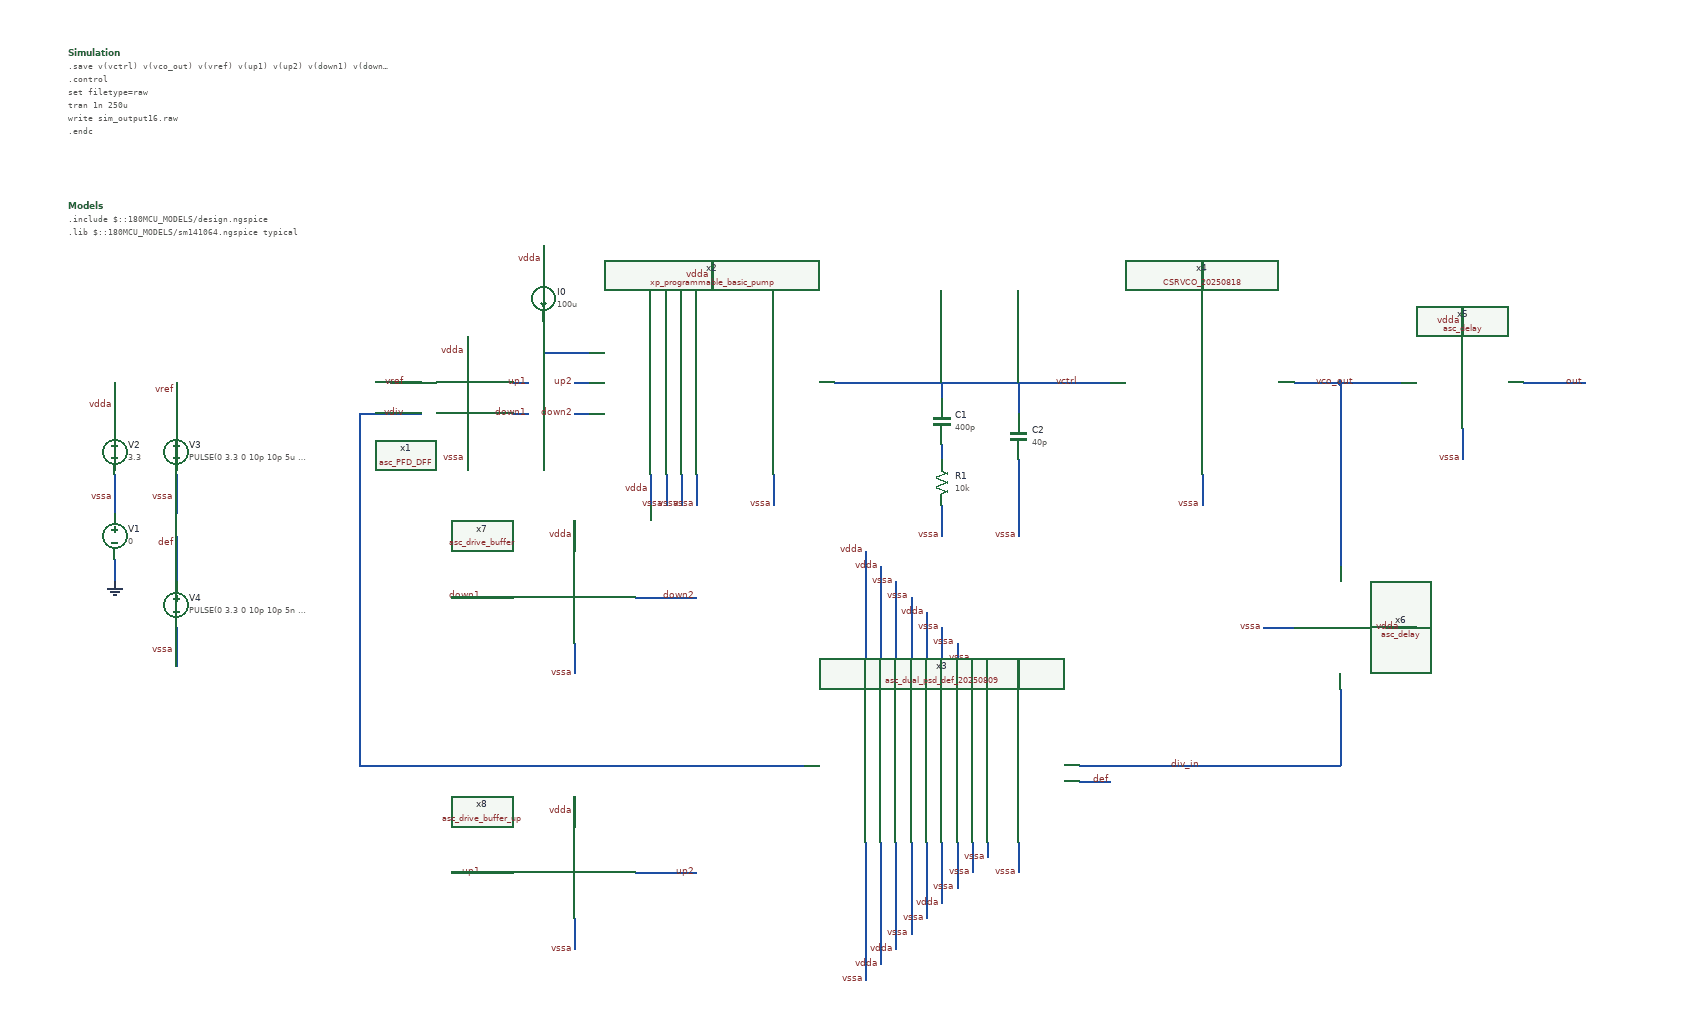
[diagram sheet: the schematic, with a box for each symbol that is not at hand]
v {xschem version=3.4.7 file_version=1.2}
G {}
K {}
V {}
S {}
E {}
N 200 -570 200 -540 {lab=GND}
N 200 -680 200 -630 {lab=vssa}
N 200 -800 200 -740 {lab=vdda}
N 280 -680 280 -630 {lab=vssa}
N 280 -800 280 -740 {lab=vref}
N 560 -800 600 -800 {lab=vref}
N 560 -760 600 -760 {lab=vdiv}
N 660 -860 660 -820 {lab=vdda}
N 660 -740 660 -700 {lab=vssa}
N 1180 -800 1220 -800 {lab=vctrl}
N 760 -880 760 -840 {lab=#net1}
N 760 -980 760 -940 {lab=vdda}
N 1740 -800 1800 -800 {lab=vco_out}
N 2040 -800 2120 -800 {lab=out}
N 1800 -800 1880 -800 {lab=vco_out}
N 1960 -900 1960 -860 {lab=vdda}
N 1960 -740 1960 -700 {lab=vssa}
N 1620 -680 1620 -640 {lab=vssa}
N 1620 -960 1620 -920 {lab=vdda}
N 1460 -800 1500 -800 {lab=vctrl}
N 520 -760 560 -760 {lab=vdiv}
N 520 -760 520 -480 {lab=vdiv}
N 1220 -800 1240 -800 {lab=vctrl}
N 1240 -800 1460 -800 {lab=vctrl}
N 1380 -700 1380 -660 {lab=vssa}
N 1280 -640 1280 -600 {lab=vssa}
N 1380 -660 1380 -600 {lab=vssa}
N 1380 -800 1380 -760 {lab=vctrl}
N 1280 -720 1280 -700 {lab=#net2}
N 1280 -800 1280 -780 {lab=vctrl}
N 1320 -200 1320 -170 {lab=vssa}
N 1320 -170 1320 -160 {lab=vssa}
N 1300 -200 1300 -160 {lab=vssa}
N 1280 -200 1280 -160 {lab=vdda}
N 1260 -200 1260 -160 {lab=vssa}
N 1240 -200 1240 -160 {lab=vssa}
N 1220 -200 1220 -160 {lab=vdda}
N 1180 -200 1180 -170 {lab=vssa}
N 1180 -170 1180 -160 {lab=vssa}
N 1200 -200 1200 -160 {lab=vdda}
N 1180 -160 1180 -60 {lab=vssa}
N 1180 -60 1180 -40 {lab=vssa}
N 1180 -40 1180 -20 {lab=vssa}
N 1200 -160 1200 -40 {lab=vdda}
N 1220 -160 1220 -60 {lab=vdda}
N 1240 -160 1240 -80 {lab=vssa}
N 1260 -160 1260 -100 {lab=vssa}
N 1280 -160 1280 -120 {lab=vdda}
N 1300 -160 1300 -140 {lab=vssa}
N 1340 -200 1340 -180 {lab=vssa}
N 1460 -300 1500 -300 {lab=div_in}
N 1460 -280 1500 -280 {lab=def}
N 1380 -440 1380 -400 {lab=vdda}
N 1380 -200 1380 -160 {lab=vssa}
N 1060 -300 1100 -300 {lab=vdiv}
N 1340 -420 1340 -400 {lab=vssa}
N 1320 -440 1320 -400 {lab=vssa}
N 1300 -460 1300 -400 {lab=vssa}
N 1280 -480 1280 -400 {lab=vssa}
N 1260 -500 1260 -400 {lab=vdda}
N 1240 -520 1240 -400 {lab=vssa}
N 1220 -540 1220 -400 {lab=vssa}
N 1200 -560 1200 -400 {lab=vdda}
N 1180 -580 1180 -400 {lab=vdda}
N 280 -480 280 -430 {lab=vssa}
N 280 -600 280 -540 {lab=def}
N 520 -480 520 -300 {lab=vdiv}
N 740 -300 1060 -300 {lab=vdiv}
N 1500 -300 1800 -300 {lab=div_in}
N 1860 -480 1900 -480 {lab=vdda}
N 1700 -480 1740 -480 {lab=vssa}
N 1800 -400 1800 -300 {lab=div_in}
N 1800 -800 1800 -560 {lab=vco_out}
N 520 -300 740 -300 {lab=vdiv}
N 760 -840 800 -840 {lab=#net1}
N 800 -840 820 -840 {lab=#net1}
N 980 -960 980 -920 {lab=vdda}
N 1060 -680 1060 -640 {lab=vssa}
N 960 -680 960 -640 {lab=vssa}
N 940 -680 940 -640 {lab=vssa}
N 920 -680 920 -640 {lab=vssa}
N 900 -680 900 -640 {lab=vdda}
N 1140 -800 1180 -800 {lab=vctrl}
N 720 -760 740 -760 {lab=down1}
N 800 -760 820 -760 {lab=down2}
N 880 -520 960 -520 {lab=down2}
N 640 -520 720 -520 {lab=down1}
N 800 -620 800 -580 {lab=vdda}
N 800 -460 800 -420 {lab=vssa}
N 720 -800 740 -800 {lab=up1}
N 800 -800 810 -800 {lab=up2}
N 810 -800 820 -800 {lab=up2}
N 880 -160 960 -160 {lab=up2}
N 640 -160 720 -160 {lab=up1}
N 800 -260 800 -220 {lab=vdda}
N 800 -100 800 -60 {lab=vssa}
C {devices/code_shown.sym} 140 -1030 0 0 {name=Models only_toplevel=false
format="tcleval( @value )"
value="
.include $::180MCU_MODELS/design.ngspice
.lib $::180MCU_MODELS/sm141064.ngspice typical
"}
C {devices/code_shown.sym} 140 -1230 0 0 {name=Simulation only_toplevel=false value="
.save v(vctrl) v(vco_out) v(vref) v(up1) v(up2) v(down1) v(down2) v(vdiv) v(x2.upb) v(div_in)

.control
set filetype=raw
tran 1n 250u
write sim_output16.raw
.endc
"}
C {devices/vsource.sym} 200 -600 0 0 {name=V1 value=0 savecurrent=false}
C {devices/gnd.sym} 200 -540 0 0 {name=l1 lab=GND}
C {devices/vsource.sym} 200 -710 0 0 {name=V2 value=3.3 savecurrent=false}
C {devices/lab_wire.sym} 200 -650 0 0 {name=p2 sig_type=std_logic lab=vssa}
C {devices/vsource.sym} 280 -710 0 0 {name=V3
value="PULSE(0 3.3 0 10p 10p 5u 10u)"
savecurrent=false}
C {devices/lab_wire.sym} 280 -650 0 0 {name=p7 sig_type=std_logic lab=vssa}
C {devices/lab_wire.sym} 200 -770 0 0 {name=p4 sig_type=std_logic lab=vdda}
C {devices/lab_wire.sym} 280 -790 0 0 {name=p8 sig_type=std_logic lab=vref}
C {libs/core_analog/asc_PFD_DFF/asc_PFD_DFF.sym} 660 -780 0 0 {name=x1}
C {devices/lab_wire.sym} 660 -700 0 0 {name=p5 sig_type=std_logic lab=vssa}
C {devices/lab_wire.sym} 660 -840 0 0 {name=p6 sig_type=std_logic lab=vdda}
C {devices/lab_wire.sym} 580 -760 0 0 {name=p9 sig_type=std_logic lab=vdiv}
C {devices/lab_wire.sym} 580 -800 0 0 {name=p10 sig_type=std_logic lab=vref}
C {devices/lab_wire.sym} 740 -800 0 0 {name=p11 sig_type=std_logic lab=up1}
C {devices/lab_wire.sym} 740 -760 0 0 {name=p12 sig_type=std_logic lab=down1}
C {devices/isource.sym} 760 -910 0 0 {name=I0 value=100u}
C {devices/lab_wire.sym} 760 -960 0 0 {name=p16 sig_type=std_logic lab=vdda
value=100u}
C {libs/core_analog/asc_delay/asc_delay.sym} 1960 -800 0 0 {name=x5}
C {devices/lab_wire.sym} 1620 -640 0 0 {name=p17 sig_type=std_logic lab=vssa}
C {devices/lab_wire.sym} 1960 -700 0 0 {name=p18 sig_type=std_logic lab=vssa}
C {devices/lab_wire.sym} 2120 -800 0 0 {name=p19 sig_type=std_logic lab=out}
C {devices/lab_wire.sym} 1620 -940 0 0 {name=p20 sig_type=std_logic lab=vdda}
C {devices/lab_wire.sym} 1960 -880 0 0 {name=p21 sig_type=std_logic lab=vdda}
C {devices/lab_wire.sym} 1460 -800 0 0 {name=p24 sig_type=std_logic lab=vctrl}
C {devices/lab_wire.sym} 1820 -800 0 0 {name=p25 sig_type=std_logic lab=vco_out}
C {devices/capa.sym} 1280 -750 0 0 {name=C1
m=1
value=400p
footprint=1206
device="ceramic capacitor"}
C {devices/capa.sym} 1380 -730 0 0 {name=C2
m=1
value=40p
footprint=1206
device="ceramic capacitor"}
C {devices/lab_wire.sym} 1380 -600 0 0 {name=p1 sig_type=std_logic lab=vssa}
C {devices/lab_wire.sym} 1280 -600 0 0 {name=p3 sig_type=std_logic lab=vssa}
C {devices/res.sym} 1280 -670 0 0 {name=R1
value=10k
footprint=1206
device=resistor
m=1}
C {devices/lab_wire.sym} 1380 -420 0 0 {name=p15 sig_type=std_logic lab=vdda}
C {devices/lab_wire.sym} 1380 -160 0 0 {name=p22 sig_type=std_logic lab=vssa}
C {devices/lab_wire.sym} 1500 -280 0 0 {name=p27 sig_type=std_logic lab=def}
C {devices/lab_wire.sym} 1340 -180 0 0 {name=p28 sig_type=std_logic lab=vssa}
C {devices/lab_wire.sym} 1320 -160 0 0 {name=p29 sig_type=std_logic lab=vssa}
C {devices/lab_wire.sym} 1300 -140 0 0 {name=p30 sig_type=std_logic lab=vssa}
C {devices/lab_wire.sym} 1280 -120 0 0 {name=p31 sig_type=std_logic lab=vdda}
C {devices/lab_wire.sym} 1260 -100 0 0 {name=p32 sig_type=std_logic lab=vssa}
C {devices/lab_wire.sym} 1240 -80 0 0 {name=p33 sig_type=std_logic lab=vssa}
C {devices/lab_wire.sym} 1220 -60 0 0 {name=p34 sig_type=std_logic lab=vdda}
C {devices/lab_wire.sym} 1200 -40 0 0 {name=p35 sig_type=std_logic lab=vdda}
C {devices/lab_wire.sym} 1180 -20 0 0 {name=p36 sig_type=std_logic lab=vssa}
C {devices/lab_wire.sym} 1340 -420 0 0 {name=p37 sig_type=std_logic lab=vssa}
C {devices/lab_wire.sym} 1320 -440 0 0 {name=p38 sig_type=std_logic lab=vssa}
C {devices/lab_wire.sym} 1300 -460 0 0 {name=p39 sig_type=std_logic lab=vssa}
C {devices/lab_wire.sym} 1280 -480 0 0 {name=p40 sig_type=std_logic lab=vssa}
C {devices/lab_wire.sym} 1260 -500 0 0 {name=p41 sig_type=std_logic lab=vdda}
C {devices/lab_wire.sym} 1240 -520 0 0 {name=p42 sig_type=std_logic lab=vssa}
C {devices/lab_wire.sym} 1220 -540 0 0 {name=p43 sig_type=std_logic lab=vssa}
C {devices/lab_wire.sym} 1200 -560 0 0 {name=p44 sig_type=std_logic lab=vdda}
C {devices/lab_wire.sym} 1180 -580 0 0 {name=p45 sig_type=std_logic lab=vdda}
C {devices/vsource.sym} 280 -510 0 0 {name=V4
value="PULSE(0 3.3 0 10p 10p 5n 1)"
savecurrent=false}
C {devices/lab_wire.sym} 280 -450 0 0 {name=p23 sig_type=std_logic lab=vssa}
C {devices/lab_wire.sym} 280 -590 0 0 {name=p26 sig_type=std_logic lab=def}
C {libs/core_analog/asc_delay/asc_delay.sym} 1800 -480 1 0 {name=x6}
C {devices/lab_wire.sym} 1700 -480 1 0 {name=p46 sig_type=std_logic lab=vssa}
C {devices/lab_wire.sym} 1880 -480 1 0 {name=p47 sig_type=std_logic lab=vdda}
C {libs/core_analog/CSRVCO_20250818/CSRVCO_20250818.sym} 1620 -800 0 0 {name=x4}
C {libs/core_analog/asc_dual_psd_def_20250809/asc_dual_psd_def_20250809.sym} 1280 -300 0 0 {name=x3}
C {libs/core_analog/xp_programmable_basic_pump/xp_programmable_basic_pump.sym} 950 -820 0 0 {name=x2}
C {devices/lab_wire.sym} 980 -940 0 0 {name=p13 sig_type=std_logic lab=vdda
value=100u}
C {devices/lab_wire.sym} 1060 -640 0 0 {name=p14 sig_type=std_logic lab=vssa}
C {devices/lab_wire.sym} 960 -640 0 0 {name=p48 sig_type=std_logic lab=vssa}
C {devices/lab_wire.sym} 940 -640 0 0 {name=p49 sig_type=std_logic lab=vssa}
C {devices/lab_wire.sym} 920 -640 0 0 {name=p50 sig_type=std_logic lab=vssa}
C {devices/lab_wire.sym} 900 -660 0 0 {name=p51 sig_type=std_logic lab=vdda
value=100u}
C {noconn.sym} 2120 -800 0 1 {name=l6}
C {devices/lab_wire.sym} 800 -760 0 0 {name=p52 sig_type=std_logic lab=down2}
C {devices/lab_wire.sym} 800 -420 0 0 {name=p53 sig_type=std_logic lab=vssa}
C {devices/lab_wire.sym} 800 -600 0 0 {name=p54 sig_type=std_logic lab=vdda}
C {devices/lab_wire.sym} 680 -520 0 0 {name=p55 sig_type=std_logic lab=down1}
C {devices/lab_wire.sym} 960 -520 0 0 {name=p56 sig_type=std_logic lab=down2}
C {libs/core_analog/asc_drive_buffer/asc_drive_buffer.sym} 800 -520 0 0 {name=x7}
C {devices/lab_wire.sym} 1620 -300 0 0 {name=p57 sig_type=std_logic lab=div_in}
C {devices/lab_wire.sym} 800 -800 0 0 {name=p58 sig_type=std_logic lab=up2}
C {devices/lab_wire.sym} 800 -60 0 0 {name=p59 sig_type=std_logic lab=vssa}
C {devices/lab_wire.sym} 800 -240 0 0 {name=p60 sig_type=std_logic lab=vdda}
C {devices/lab_wire.sym} 680 -160 0 0 {name=p61 sig_type=std_logic lab=up1}
C {devices/lab_wire.sym} 960 -160 0 0 {name=p62 sig_type=std_logic lab=up2}
C {libs/core_analog/asc_drive_buffer_up/asc_drive_buffer_up.sym} 800 -160 0 0 {name=x8}
